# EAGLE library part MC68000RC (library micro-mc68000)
68xxx PROCESSOR

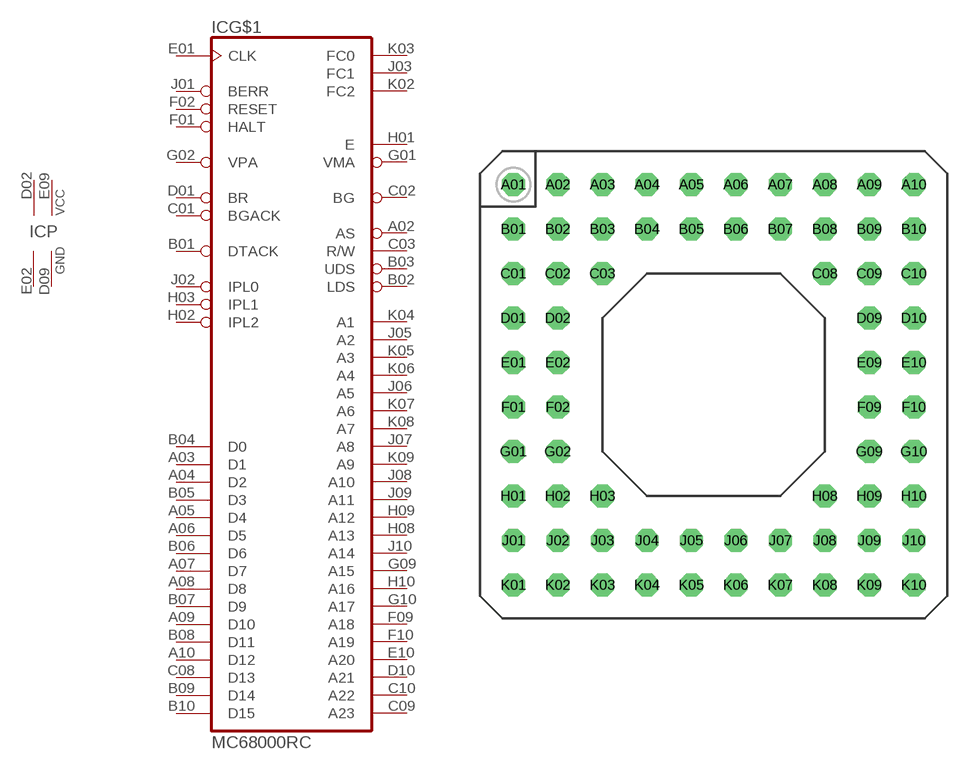
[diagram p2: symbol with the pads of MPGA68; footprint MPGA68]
Designator prefix IC; gates G$1=68000 P=2PWR2GND

## MC68000RC (MF: MOTOROLA; MPN: MC68HC000RC16; OC_FARNELL: unknown; OC_NEWARK: 40K0242)  [MPGA68]
A02  G$1:AS  out
A03  G$1:D1
A04  G$1:D2
A05  G$1:D4
A06  G$1:D5
A07  G$1:D7
A08  G$1:D8
A09  G$1:D10
A10  G$1:D12
B01  G$1:DTACK  in
B02  G$1:LDS  out
B03  G$1:UDS  out
B04  G$1:D0
B05  G$1:D3
B06  G$1:D6
B07  G$1:D9
B08  G$1:D11
B09  G$1:D14
B10  G$1:D15
C01  G$1:BGACK  in
C02  G$1:BG  out
C03  G$1:R/W  out
C08  G$1:D13
C09  G$1:A23  out
C10  G$1:A22  out
D01  G$1:BR  in
D02  P:VCC  pwr
D09  P:GND  pwr
D10  G$1:A21  out
E01  G$1:CLK  in
E02  P:GND  pwr
E09  P:VCC  pwr
E10  G$1:A20  out
F01  G$1:HALT
F02  G$1:RESET
F09  G$1:A18  out
F10  G$1:A19  out
G01  G$1:VMA  out
G02  G$1:VPA  in
G09  G$1:A15  out
G10  G$1:A17  out
H01  G$1:E  out
H02  G$1:IPL2  in
H03  G$1:IPL1  in
H08  G$1:A13  out
H09  G$1:A12  out
H10  G$1:A16  out
J01  G$1:BERR  in
J02  G$1:IPL0  in
J03  G$1:FC1  out
J05  G$1:A2  out
J06  G$1:A5  out
J07  G$1:A8  out
J08  G$1:A10  out
J09  G$1:A11  out
J10  G$1:A14  out
K02  G$1:FC2  out
K03  G$1:FC0  out
K04  G$1:A1  out
K05  G$1:A3  out
K06  G$1:A4  out
K07  G$1:A6  out
K08  G$1:A7  out
K09  G$1:A9  out

## Footprint MPGA68 (pad centres in mm)
micro Ball Grid Array
drill 0.813 octagon: A01 -11.43,11.43; A02 -8.89,11.43; A03 -6.35,11.43; A04 -3.81,11.43; A05 -1.27,11.43; A06 1.27,11.43; A07 3.81,11.43; A08 6.35,11.43; A09 8.89,11.43; A10 11.43,11.43; B01 -11.43,8.89; B02 -8.89,8.89; B03 -6.35,8.89; B04 -3.81,8.89; B05 -1.27,8.89; B06 1.27,8.89; B07 3.81,8.89; B08 6.35,8.89; B09 8.89,8.89; B10 11.43,8.89; C01 -11.43,6.35; C02 -8.89,6.35; C03 -6.35,6.35; C08 6.35,6.35; C09 8.89,6.35; C10 11.43,6.35; D01 -11.43,3.81; D02 -8.89,3.81; D09 8.89,3.81; D10 11.43,3.81; E01 -11.43,1.27; E02 -8.89,1.27; E09 8.89,1.27; E10 11.43,1.27; F01 -11.43,-1.27; F02 -8.89,-1.27; F09 8.89,-1.27; F10 11.43,-1.27; G01 -11.43,-3.81; G02 -8.89,-3.81; G09 8.89,-3.81; G10 11.43,-3.81; H01 -11.43,-6.35; H02 -8.89,-6.35; H03 -6.35,-6.35; H08 6.35,-6.35; H09 8.89,-6.35; H10 11.43,-6.35; J01 -11.43,-8.89; J02 -8.89,-8.89; J03 -6.35,-8.89; J04 -3.81,-8.89; J05 -1.27,-8.89; J06 1.27,-8.89; J07 3.81,-8.89; J08 6.35,-8.89; J09 8.89,-8.89; J10 11.43,-8.89; K01 -11.43,-11.43; K02 -8.89,-11.43; K03 -6.35,-11.43; K04 -3.81,-11.43; K05 -1.27,-11.43; K06 1.27,-11.43; K07 3.81,-11.43; K08 6.35,-11.43; K09 8.89,-11.43; K10 11.43,-11.43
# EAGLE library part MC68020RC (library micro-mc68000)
68xxx PROCESSOR

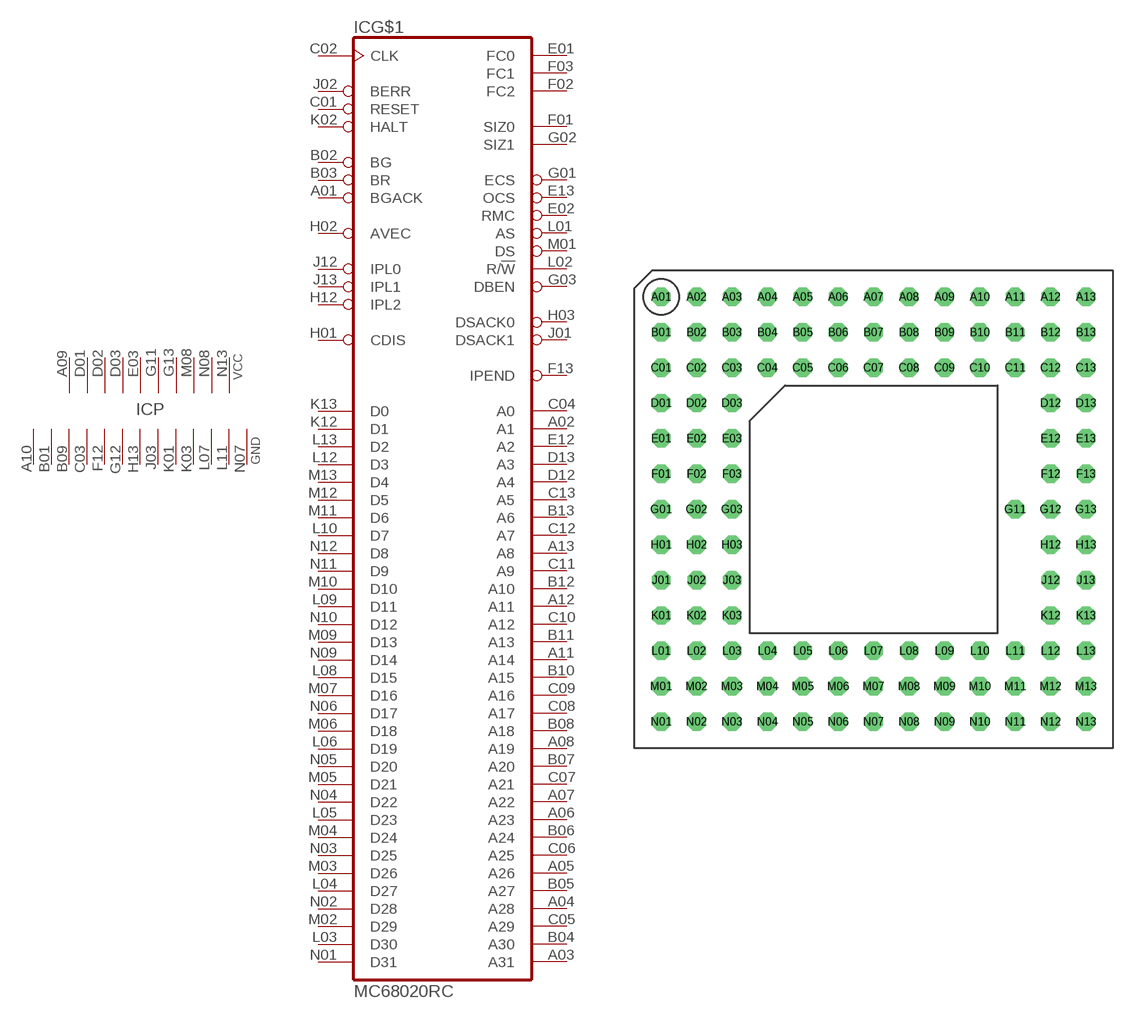
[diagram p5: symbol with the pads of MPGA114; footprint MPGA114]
Designator prefix IC; gates G$1=68020 P=10PW13GN

## MC68020RC (MF: MOTOROLA; MPN: MC68020RC33E; OC_FARNELL: 1579779; OC_NEWARK: 66F7091)  [MPGA114]
A01  G$1:BGACK  in
A02  G$1:A1  out
A03  G$1:A31  out
A04  G$1:A28  out
A05  G$1:A26  out
A06  G$1:A23  out
A07  G$1:A22  out
A08  G$1:A19  out
A09  P:VCC  pwr
A10  P:GND  pwr
A11  G$1:A14  out
A12  G$1:A11  out
A13  G$1:A8  out
B01  P:GND  pwr
B02  G$1:BG  out
B03  G$1:BR  in
B04  G$1:A30  out
B05  G$1:A27  out
B06  G$1:A24  out
B07  G$1:A20  out
B08  G$1:A18  out
B09  P:GND  pwr
B10  G$1:A15  out
B11  G$1:A13  out
B12  G$1:A10  out
B13  G$1:A6  out
C01  G$1:RESET
C02  G$1:CLK  in
C03  P:GND  pwr
C04  G$1:A0  out
C05  G$1:A29  out
C06  G$1:A25  out
C07  G$1:A21  out
C08  G$1:A17  out
C09  G$1:A16  out
C10  G$1:A12  out
C11  G$1:A9  out
C12  G$1:A7  out
C13  G$1:A5  out
D01  P:VCC  pwr
D02  P:VCC  pwr
D03  P:VCC  pwr
D12  G$1:A4  out
D13  G$1:A3  out
E01  G$1:FC0  out
E02  G$1:RMC  out
E03  P:VCC  pwr
E12  G$1:A2  out
E13  G$1:OCS  out
F01  G$1:SIZ0  out
F02  G$1:FC2  out
F03  G$1:FC1  out
F12  P:GND  pwr
F13  G$1:IPEND  out
G01  G$1:ECS  out
G02  G$1:SIZ1  out
G03  G$1:DBEN  out
G11  P:VCC  pwr
G12  P:GND  pwr
G13  P:VCC  pwr
H01  G$1:CDIS  in
H02  G$1:AVEC  in
H03  G$1:DSACK0  in
H12  G$1:IPL2  in
H13  P:GND  pwr
J01  G$1:DSACK1  in
J02  G$1:BERR  in
J03  P:GND  pwr
J12  G$1:IPL0  in
J13  G$1:IPL1  in
K01  P:GND  pwr
K02  G$1:HALT
K03  P:GND  pwr
K12  G$1:D1
K13  G$1:D0
L01  G$1:AS  out
L02  G$1:R/!W  out
L03  G$1:D30
L04  G$1:D27
L05  G$1:D23
L06  G$1:D19
L07  P:GND  pwr
L08  G$1:D15
L09  G$1:D11
L10  G$1:D7
L11  P:GND  pwr
L12  G$1:D3
L13  G$1:D2
M01  G$1:DS  out
M02  G$1:D29
M03  G$1:D26
M04  G$1:D24
M05  G$1:D21
M06  G$1:D18
M07  G$1:D16
M08  P:VCC  pwr
M09  G$1:D13
M10  G$1:D10
M11  G$1:D6
M12  G$1:D5
M13  G$1:D4
N01  G$1:D31
N02  G$1:D28
N03  G$1:D25
N04  G$1:D22
N05  G$1:D20
N06  G$1:D17
N07  P:GND  pwr
N08  P:VCC  pwr
N09  G$1:D14
N10  G$1:D12
N11  G$1:D9
N12  G$1:D8
N13  P:VCC  pwr

## Footprint MPGA114 (pad centres in mm)
micro Ball Grid Array
drill 0.813 octagon: A01 -15.24,15.24; A02 -12.7,15.24; A03 -10.16,15.24; A04 -7.62,15.24; A05 -5.08,15.24; A06 -2.54,15.24; A07 0,15.24; A08 2.54,15.24; A09 5.08,15.24; A10 7.62,15.24; A11 10.16,15.24; A12 12.7,15.24; A13 15.24,15.24; B01 -15.24,12.7; B02 -12.7,12.7; B03 -10.16,12.7; B04 -7.62,12.7; B05 -5.08,12.7; B06 -2.54,12.7; B07 0,12.7; B08 2.54,12.7; B09 5.08,12.7; B10 7.62,12.7; B11 10.16,12.7; B12 12.7,12.7; B13 15.24,12.7; C01 -15.24,10.16; C02 -12.7,10.16; C03 -10.16,10.16; C04 -7.62,10.16; C05 -5.08,10.16; C06 -2.54,10.16; C07 0,10.16; C08 2.54,10.16; C09 5.08,10.16; C10 7.62,10.16; C11 10.16,10.16; C12 12.7,10.16; C13 15.24,10.16; D01 -15.24,7.62; D02 -12.7,7.62; D03 -10.16,7.62; D12 12.7,7.62; D13 15.24,7.62; E01 -15.24,5.08; E02 -12.7,5.08; E03 -10.16,5.08; E12 12.7,5.08; E13 15.24,5.08; F01 -15.24,2.54; F02 -12.7,2.54; F03 -10.16,2.54; F12 12.7,2.54; F13 15.24,2.54; G01 -15.24,0; G02 -12.7,0; G03 -10.16,0; G11 10.16,0; G12 12.7,0; G13 15.24,0; H01 -15.24,-2.54; H02 -12.7,-2.54; H03 -10.16,-2.54; H12 12.7,-2.54; H13 15.24,-2.54; J01 -15.24,-5.08; J02 -12.7,-5.08; J03 -10.16,-5.08; J12 12.7,-5.08; J13 15.24,-5.08; K01 -15.24,-7.62; K02 -12.7,-7.62; K03 -10.16,-7.62; K12 12.7,-7.62; K13 15.24,-7.62; L01 -15.24,-10.16; L02 -12.7,-10.16; L03 -10.16,-10.16; L04 -7.62,-10.16; L05 -5.08,-10.16; L06 -2.54,-10.16; L07 0,-10.16; L08 2.54,-10.16; L09 5.08,-10.16; L10 7.62,-10.16; L11 10.16,-10.16; L12 12.7,-10.16; L13 15.24,-10.16; M01 -15.24,-12.7; M02 -12.7,-12.7; M03 -10.16,-12.7; M04 -7.62,-12.7; M05 -5.08,-12.7; M06 -2.54,-12.7; M07 0,-12.7; M08 2.54,-12.7; M09 5.08,-12.7; M10 7.62,-12.7; M11 10.16,-12.7; M12 12.7,-12.7; M13 15.24,-12.7; N01 -15.24,-15.24; N02 -12.7,-15.24; N03 -10.16,-15.24; N04 -7.62,-15.24; N05 -5.08,-15.24; N06 -2.54,-15.24; N07 0,-15.24; N08 2.54,-15.24; N09 5.08,-15.24; N10 7.62,-15.24; N11 10.16,-15.24; N12 12.7,-15.24; N13 15.24,-15.24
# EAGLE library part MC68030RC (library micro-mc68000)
68xxx PROCESSOR

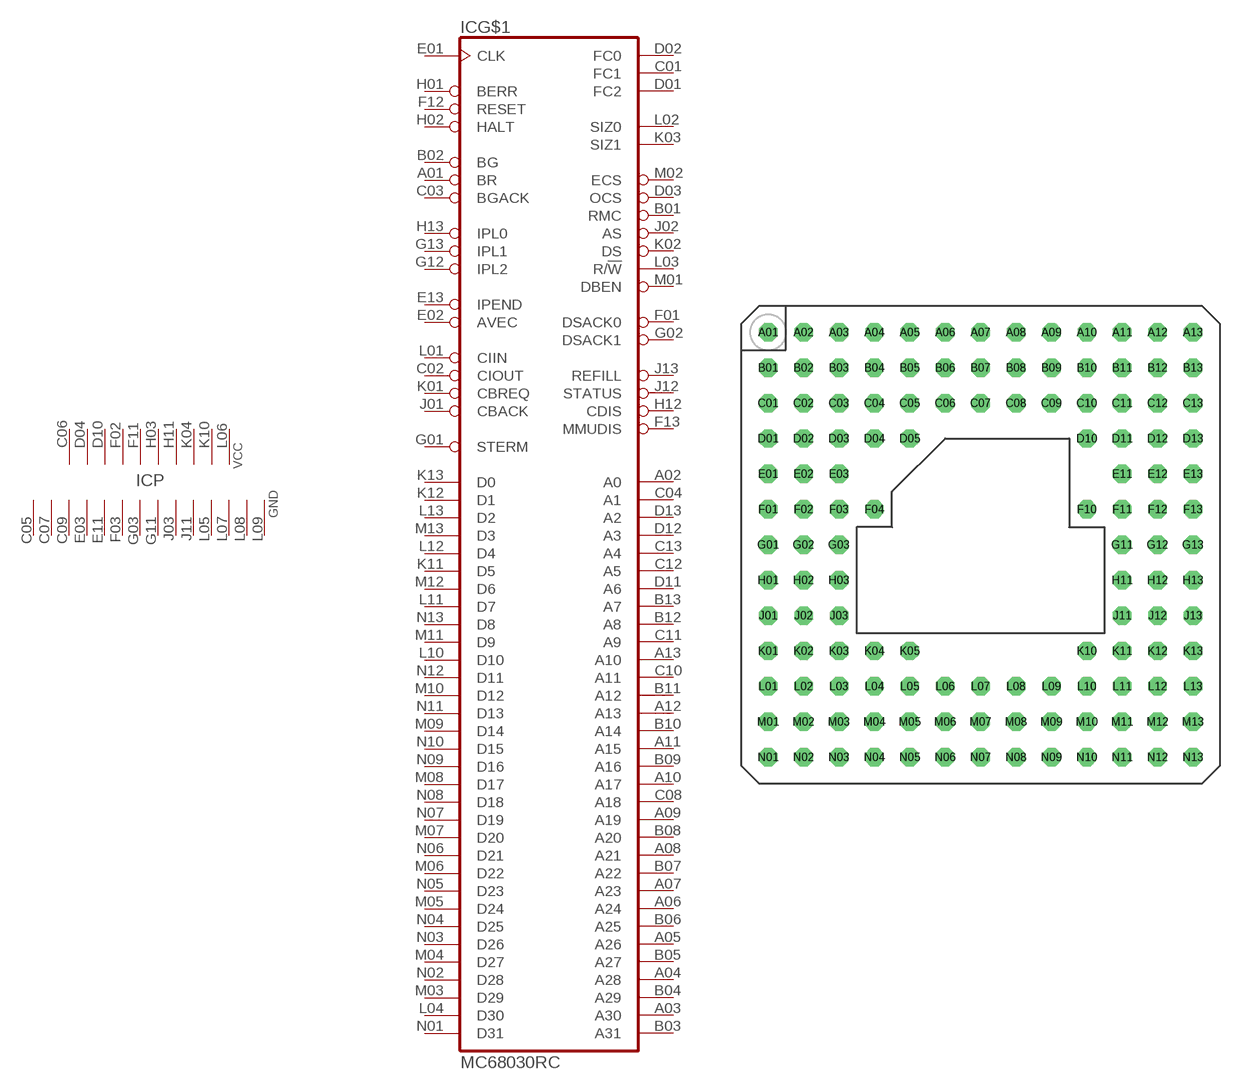
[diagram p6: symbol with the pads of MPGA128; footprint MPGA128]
Designator prefix IC; gates G$1=68030 P=10PW14GN

## MC68030RC (MF: MOTOROLA; MPN: MC68030RC50C; OC_FARNELL: unknown; OC_NEWARK: 52F3269)  [MPGA128]
A01  G$1:BR  in
A02  G$1:A0  out
A03  G$1:A30  out
A04  G$1:A28  out
A05  G$1:A26  out
A06  G$1:A24  out
A07  G$1:A23  out
A08  G$1:A21  out
A09  G$1:A19  out
A10  G$1:A17  out
A11  G$1:A15  out
A12  G$1:A13  out
A13  G$1:A10  out
B01  G$1:RMC  out
B02  G$1:BG  out
B03  G$1:A31  out
B04  G$1:A29  out
B05  G$1:A27  out
B06  G$1:A25  out
B07  G$1:A22  out
B08  G$1:A20  out
B09  G$1:A16  out
B10  G$1:A14  out
B11  G$1:A12  out
B12  G$1:A8  out
B13  G$1:A7  out
C01  G$1:FC1  out
C02  G$1:CIOUT  out
C03  G$1:BGACK  in
C04  G$1:A1  out
C05  P:GND  pwr
C06  P:VCC  pwr
C07  P:GND  pwr
C08  G$1:A18  out
C09  P:GND  pwr
C10  G$1:A11  out
C11  G$1:A9  out
C12  G$1:A5  out
C13  G$1:A4  out
D01  G$1:FC2  out
D02  G$1:FC0  out
D03  G$1:OCS  out
D04  P:VCC  pwr
D10  P:VCC  pwr
D11  G$1:A6  out
D12  G$1:A3  out
D13  G$1:A2  out
E01  G$1:CLK  in
E02  G$1:AVEC  in
E03  P:GND  pwr
E11  P:GND  pwr
E13  G$1:IPEND  out
F01  G$1:DSACK0  in
F02  P:VCC  pwr
F03  P:GND  pwr
F11  P:VCC  pwr
F12  G$1:RESET
F13  G$1:MMUDIS  in
G01  G$1:STERM  in
G02  G$1:DSACK1  in
G03  P:GND  pwr
G11  P:GND  pwr
G12  G$1:IPL2  in
G13  G$1:IPL1  in
H01  G$1:BERR  in
H02  G$1:HALT  in
H03  P:VCC  pwr
H11  P:VCC  pwr
H12  G$1:CDIS  in
H13  G$1:IPL0  in
J01  G$1:CBACK  in
J02  G$1:AS  out
J03  P:GND  pwr
J11  P:GND  pwr
J12  G$1:STATUS  out
J13  G$1:REFILL  out
K01  G$1:CBREQ  out
K02  G$1:DS  out
K03  G$1:SIZ1  out
K04  P:VCC  pwr
K10  P:VCC  pwr
K11  G$1:D5
K12  G$1:D1
K13  G$1:D0
L01  G$1:CIIN  in
L02  G$1:SIZ0  out
L03  G$1:R/!W  out
L04  G$1:D30
L05  P:GND  pwr
L06  P:VCC  pwr
L07  P:GND  pwr
L08  P:GND  pwr
L09  P:GND  pwr
L10  G$1:D10
L11  G$1:D7
L12  G$1:D4
L13  G$1:D2
M01  G$1:DBEN  out
M02  G$1:ECS  out
M03  G$1:D29
M04  G$1:D27
M05  G$1:D24
M06  G$1:D22
M07  G$1:D20
M08  G$1:D17
M09  G$1:D14
M10  G$1:D12
M11  G$1:D9
M12  G$1:D6
M13  G$1:D3
N01  G$1:D31
N02  G$1:D28
N03  G$1:D26
N04  G$1:D25
N05  G$1:D23
N06  G$1:D21
N07  G$1:D19
N08  G$1:D18
N09  G$1:D16
N10  G$1:D15
N11  G$1:D13
N12  G$1:D11
N13  G$1:D8

## Footprint MPGA128 (pad centres in mm)
micro Ball Grid Array
drill 0.813 octagon: A01 -15.24,15.24; A02 -12.7,15.24; A03 -10.16,15.24; A04 -7.62,15.24; A05 -5.08,15.24; A06 -2.54,15.24; A07 0,15.24; A08 2.54,15.24; A09 5.08,15.24; A10 7.62,15.24; A11 10.16,15.24; A12 12.7,15.24; A13 15.24,15.24; B01 -15.24,12.7; B02 -12.7,12.7; B03 -10.16,12.7; B04 -7.62,12.7; B05 -5.08,12.7; B06 -2.54,12.7; B07 0,12.7; B08 2.54,12.7; B09 5.08,12.7; B10 7.62,12.7; B11 10.16,12.7; B12 12.7,12.7; B13 15.24,12.7; C01 -15.24,10.16; C02 -12.7,10.16; C03 -10.16,10.16; C04 -7.62,10.16; C05 -5.08,10.16; C06 -2.54,10.16; C07 0,10.16; C08 2.54,10.16; C09 5.08,10.16; C10 7.62,10.16; C11 10.16,10.16; C12 12.7,10.16; C13 15.24,10.16; D01 -15.24,7.62; D02 -12.7,7.62; D03 -10.16,7.62; D04 -7.62,7.62; D05 -5.08,7.62; D10 7.62,7.62; D11 10.16,7.62; D12 12.7,7.62; D13 15.24,7.62; E01 -15.24,5.08; E02 -12.7,5.08; E03 -10.16,5.08; E11 10.16,5.08; E12 12.7,5.08; E13 15.24,5.08; F01 -15.24,2.54; F02 -12.7,2.54; F03 -10.16,2.54; F04 -7.62,2.54; F10 7.62,2.54; F11 10.16,2.54; F12 12.7,2.54; F13 15.24,2.54; G01 -15.24,0; G02 -12.7,0; G03 -10.16,0; G11 10.16,0; G12 12.7,0; G13 15.24,0; H01 -15.24,-2.54; H02 -12.7,-2.54; H03 -10.16,-2.54; H11 10.16,-2.54; H12 12.7,-2.54; H13 15.24,-2.54; J01 -15.24,-5.08; J02 -12.7,-5.08; J03 -10.16,-5.08; J11 10.16,-5.08; J12 12.7,-5.08; J13 15.24,-5.08; K01 -15.24,-7.62; K02 -12.7,-7.62; K03 -10.16,-7.62; K04 -7.62,-7.62; K05 -5.08,-7.62; K10 7.62,-7.62; K11 10.16,-7.62; K12 12.7,-7.62; K13 15.24,-7.62; L01 -15.24,-10.16; L02 -12.7,-10.16; L03 -10.16,-10.16; L04 -7.62,-10.16; L05 -5.08,-10.16; L06 -2.54,-10.16; L07 0,-10.16; L08 2.54,-10.16; L09 5.08,-10.16; L10 7.62,-10.16; L11 10.16,-10.16; L12 12.7,-10.16; L13 15.24,-10.16; M01 -15.24,-12.7; M02 -12.7,-12.7; M03 -10.16,-12.7; M04 -7.62,-12.7; M05 -5.08,-12.7; M06 -2.54,-12.7; M07 0,-12.7; M08 2.54,-12.7; M09 5.08,-12.7; M10 7.62,-12.7; M11 10.16,-12.7; M12 12.7,-12.7; M13 15.24,-12.7; N01 -15.24,-15.24; N02 -12.7,-15.24; N03 -10.16,-15.24; N04 -7.62,-15.24; N05 -5.08,-15.24; N06 -2.54,-15.24; N07 0,-15.24; N08 2.54,-15.24; N09 5.08,-15.24; N10 7.62,-15.24; N11 10.16,-15.24; N12 12.7,-15.24; N13 15.24,-15.24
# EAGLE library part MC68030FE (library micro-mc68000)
68xxx PROCESSOR

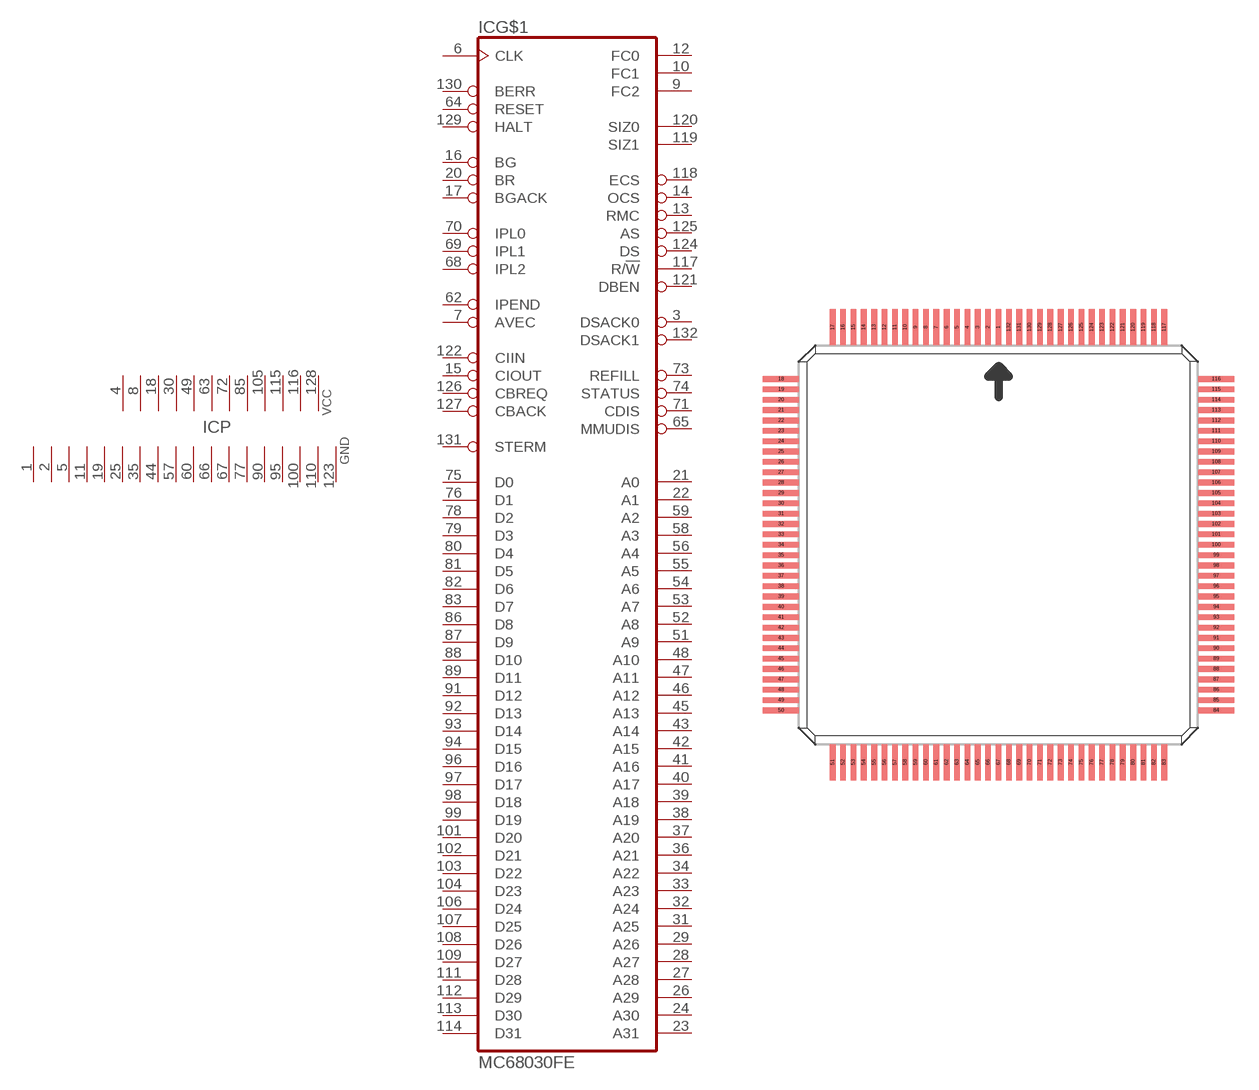
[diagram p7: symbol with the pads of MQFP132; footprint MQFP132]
Designator prefix IC; gates G$1=68030 P=12PW18GN

## MC68030FE (MF: MOTOROLA; MPN: MC68030FE33C; OC_FARNELL: unknown; OC_NEWARK: 52F3266)  [MQFP132]
1  P:GND  pwr
2  P:GND  pwr
3  G$1:DSACK0  in
4  P:VCC  pwr
5  P:GND  pwr
6  G$1:CLK  in
7  G$1:AVEC  in
8  P:VCC  pwr
9  G$1:FC2  out
10  G$1:FC1  out
11  P:GND  pwr
12  G$1:FC0  out
13  G$1:RMC  out
14  G$1:OCS  out
15  G$1:CIOUT  out
16  G$1:BG  out
17  G$1:BGACK  in
18  P:VCC  pwr
19  P:GND  pwr
20  G$1:BR  in
21  G$1:A0  out
22  G$1:A1  out
23  G$1:A31  out
24  G$1:A30  out
25  P:GND  pwr
26  G$1:A29  out
27  G$1:A28  out
28  G$1:A27  out
29  G$1:A26  out
30  P:VCC  pwr
31  G$1:A25  out
32  G$1:A24  out
33  G$1:A23  out
34  G$1:A22  out
35  P:GND  pwr
36  G$1:A21  out
37  G$1:A20  out
38  G$1:A19  out
39  G$1:A18  out
40  G$1:A17  out
41  G$1:A16  out
42  G$1:A15  out
43  G$1:A14  out
44  P:GND  pwr
45  G$1:A13  out
46  G$1:A12  out
47  G$1:A11  out
48  G$1:A10  out
49  P:VCC  pwr
51  G$1:A9  out
52  G$1:A8  out
53  G$1:A7  out
54  G$1:A6  out
55  G$1:A5  out
56  G$1:A4  out
57  P:GND  pwr
58  G$1:A3  out
59  G$1:A2  out
60  P:GND  pwr
62  G$1:IPEND  out
63  P:VCC  pwr
64  G$1:RESET
65  G$1:MMUDIS  in
66  P:GND  pwr
67  P:GND  pwr
68  G$1:IPL2  in
69  G$1:IPL1  in
70  G$1:IPL0  in
71  G$1:CDIS  in
72  P:VCC  pwr
73  G$1:REFILL  out
74  G$1:STATUS  out
75  G$1:D0
76  G$1:D1
77  P:GND  pwr
78  G$1:D2
79  G$1:D3
80  G$1:D4
81  G$1:D5
82  G$1:D6
83  G$1:D7
85  P:VCC  pwr
86  G$1:D8
87  G$1:D9
88  G$1:D10
89  G$1:D11
90  P:GND  pwr
91  G$1:D12
92  G$1:D13
93  G$1:D14
94  G$1:D15
95  P:GND  pwr
96  G$1:D16
97  G$1:D17
98  G$1:D18
99  G$1:D19
100  P:GND  pwr
101  G$1:D20
102  G$1:D21
103  G$1:D22
104  G$1:D23
105  P:VCC  pwr
106  G$1:D24
107  G$1:D25
108  G$1:D26
109  G$1:D27
110  P:GND  pwr
111  G$1:D28
112  G$1:D29
113  G$1:D30
114  G$1:D31
115  P:VCC  pwr
116  P:VCC  pwr
117  G$1:R/!W  out
118  G$1:ECS  out
119  G$1:SIZ1  out
120  G$1:SIZ0  out
121  G$1:DBEN  out
122  G$1:CIIN  in
123  P:GND  pwr
124  G$1:DS  out
125  G$1:AS  out
126  G$1:CBREQ  out
127  G$1:CBACK  in
128  P:VCC  pwr
129  G$1:HALT  in
130  G$1:BERR  in
131  G$1:STERM  in
132  G$1:DSACK1  in

## Footprint MQFP132 (pad centres in mm)
Metric Quad Flat Pack
smd 0.35 x 2.2: 1 0,12.7; 2 -0.635,12.7; 3 -1.27,12.7; 4 -1.905,12.7; 5 -2.54,12.7; 6 -3.175,12.7; 7 -3.81,12.7; 8 -4.445,12.7; 9 -5.08,12.7; 10 -5.715,12.7; 11 -6.35,12.7; 12 -6.985,12.7; 13 -7.62,12.7; 14 -8.255,12.7; 15 -8.89,12.7; 16 -9.525,12.7; 17 -10.16,12.7; 51 -10.16,-13.97; 52 -9.525,-13.97; 53 -8.89,-13.97; 54 -8.255,-13.97; 55 -7.62,-13.97; 56 -6.985,-13.97; 57 -6.35,-13.97; 58 -5.715,-13.97; 59 -5.08,-13.97; 60 -4.445,-13.97; 61 -3.81,-13.97; 62 -3.175,-13.97; 63 -2.54,-13.97; 64 -1.905,-13.97; 65 -1.27,-13.97; 66 -0.635,-13.97; 67 0,-13.97; 68 0.635,-13.97; 69 1.27,-13.97; 70 1.905,-13.97; 71 2.54,-13.97; 72 3.175,-13.97; 73 3.81,-13.97; 74 4.445,-13.97; 75 5.08,-13.97; 76 5.715,-13.97; 77 6.35,-13.97; 78 6.985,-13.97; 79 7.62,-13.97; 80 8.255,-13.97; 81 8.89,-13.97; 82 9.525,-13.97; 83 10.16,-13.97; 117 10.16,12.7; 118 9.525,12.7; 119 8.89,12.7; 120 8.255,12.7; 121 7.62,12.7; 122 6.985,12.7; 123 6.35,12.7; 124 5.715,12.7; 125 5.08,12.7; 126 4.445,12.7; 127 3.81,12.7; 128 3.175,12.7; 129 2.54,12.7; 130 1.905,12.7; 131 1.27,12.7; 132 0.635,12.7
smd 2.2 x 0.35: 18 -13.335,9.525; 19 -13.335,8.89; 20 -13.335,8.255; 21 -13.335,7.62; 22 -13.335,6.985; 23 -13.335,6.35; 24 -13.335,5.715; 25 -13.335,5.08; 26 -13.335,4.445; 27 -13.335,3.81; 28 -13.335,3.175; 29 -13.335,2.54; 30 -13.335,1.905; 31 -13.335,1.27; 32 -13.335,0.635; 33 -13.335,0; 34 -13.335,-0.635; 35 -13.335,-1.27; 36 -13.335,-1.905; 37 -13.335,-2.54; 38 -13.335,-3.175; 39 -13.335,-3.81; 40 -13.335,-4.445; 41 -13.335,-5.08; 42 -13.335,-5.715; 43 -13.335,-6.35; 44 -13.335,-6.985; 45 -13.335,-7.62; 46 -13.335,-8.255; 47 -13.335,-8.89; 48 -13.335,-9.525; 49 -13.335,-10.16; 50 -13.335,-10.795; 84 13.335,-10.795; 85 13.335,-10.16; 86 13.335,-9.525; 87 13.335,-8.89; 88 13.335,-8.255; 89 13.335,-7.62; 90 13.335,-6.985; 91 13.335,-6.35; 92 13.335,-5.715; 93 13.335,-5.08; 94 13.335,-4.445; 95 13.335,-3.81; 96 13.335,-3.175; 97 13.335,-2.54; 98 13.335,-1.905; 99 13.335,-1.27; 100 13.335,-0.635; 101 13.335,0; 102 13.335,0.635; 103 13.335,1.27; 104 13.335,1.905; 105 13.335,2.54; 106 13.335,3.175; 107 13.335,3.81; 108 13.335,4.445; 109 13.335,5.08; 110 13.335,5.715; 111 13.335,6.35; 112 13.335,6.985; 113 13.335,7.62; 114 13.335,8.255; 115 13.335,8.89; 116 13.335,9.525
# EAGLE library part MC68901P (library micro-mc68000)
68xxx PROCESSOR

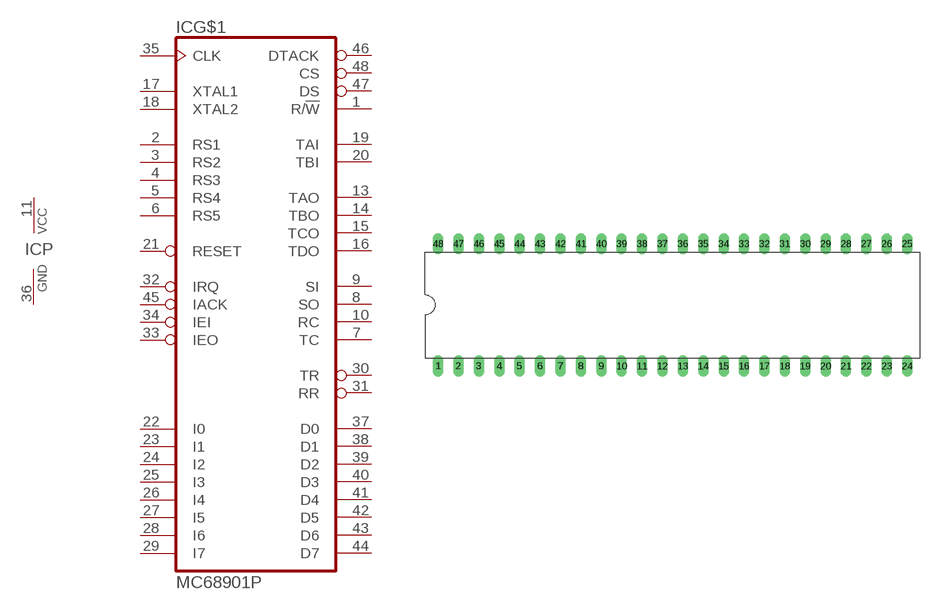
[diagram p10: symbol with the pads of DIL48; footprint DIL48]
Designator prefix IC; gates G$1=68901 P=PWRN

## MC68901P (OC_FARNELL: unknown; OC_NEWARK: unknown)  [DIL48]
1  G$1:R/!W  in
2  G$1:RS1  in
3  G$1:RS2  in
4  G$1:RS3  in
5  G$1:RS4  in
6  G$1:RS5  in
7  G$1:TC  in
8  G$1:SO  out
9  G$1:SI  in
10  G$1:RC  in
11  P:VCC  pwr
13  G$1:TAO  out
14  G$1:TBO  out
15  G$1:TCO  out
16  G$1:TDO  out
17  G$1:XTAL1  in
18  G$1:XTAL2  in
19  G$1:TAI  in
20  G$1:TBI  in
21  G$1:RESET  in
22  G$1:I0
23  G$1:I1
24  G$1:I2
25  G$1:I3
26  G$1:I4
27  G$1:I5
28  G$1:I6
29  G$1:I7
30  G$1:TR  out
31  G$1:RR  out
32  G$1:IRQ  out
33  G$1:IEO  out
34  G$1:IEI  in
35  G$1:CLK  in
36  P:GND  pwr
37  G$1:D0
38  G$1:D1
39  G$1:D2
40  G$1:D3
41  G$1:D4
42  G$1:D5
43  G$1:D6
44  G$1:D7
45  G$1:IACK  in
46  G$1:DTACK  out
47  G$1:DS  in
48  G$1:CS  in

## Footprint DIL48 (pad centres in mm)
Dual In Line
drill 0.813 long: 1 -29.21,-7.62; 2 -26.67,-7.62; 3 -24.13,-7.62; 4 -21.59,-7.62; 5 -19.05,-7.62; 6 -16.51,-7.62; 7 -13.97,-7.62; 8 -11.43,-7.62; 9 -8.89,-7.62; 10 -6.35,-7.62; 11 -3.81,-7.62; 12 -1.27,-7.62; 13 1.27,-7.62; 14 3.81,-7.62; 15 6.35,-7.62; 16 8.89,-7.62; 17 11.43,-7.62; 18 13.97,-7.62; 19 16.51,-7.62; 20 19.05,-7.62; 21 21.59,-7.62; 22 24.13,-7.62; 23 26.67,-7.62; 24 29.21,-7.62; 25 29.21,7.62; 26 26.67,7.62; 27 24.13,7.62; 28 21.59,7.62; 29 19.05,7.62; 30 16.51,7.62; 31 13.97,7.62; 32 11.43,7.62; 33 8.89,7.62; 34 6.35,7.62; 35 3.81,7.62; 36 1.27,7.62; 37 -1.27,7.62; 38 -3.81,7.62; 39 -6.35,7.62; 40 -8.89,7.62; 41 -11.43,7.62; 42 -13.97,7.62; 43 -16.51,7.62; 44 -19.05,7.62; 45 -21.59,7.62; 46 -24.13,7.62; 47 -26.67,7.62; 48 -29.21,7.62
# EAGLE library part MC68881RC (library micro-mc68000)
68xxx PROCESSOR

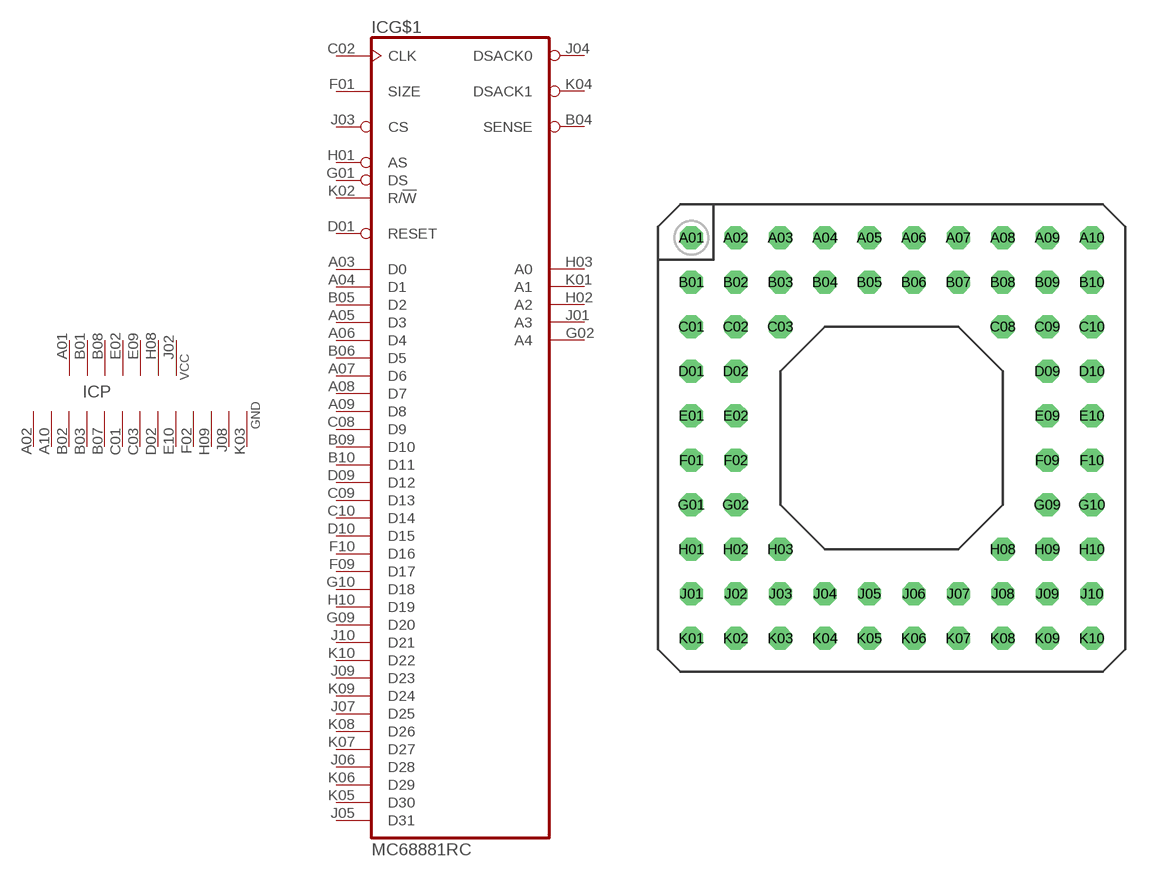
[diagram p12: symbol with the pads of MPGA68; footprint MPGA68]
Designator prefix IC; gates G$1=68881 P=7PWR13GN

## MC68881RC (OC_FARNELL: unknown; OC_NEWARK: unknown)  [MPGA68]
A01  P:VCC  pwr
A02  P:GND  pwr
A03  G$1:D0
A04  G$1:D1
A05  G$1:D3
A06  G$1:D4
A07  G$1:D6
A08  G$1:D7
A09  G$1:D8
A10  P:GND  pwr
B01  P:VCC  pwr
B02  P:GND  pwr
B03  P:GND  pwr
B04  G$1:SENSE
B05  G$1:D2
B06  G$1:D5
B07  P:GND  pwr
B08  P:VCC  pwr
B09  G$1:D10
B10  G$1:D11
C01  P:GND  pwr
C02  G$1:CLK  in
C03  P:GND  pwr
C08  G$1:D9
C09  G$1:D13
C10  G$1:D14
D01  G$1:RESET  in
D02  P:GND  pwr
D09  G$1:D12
D10  G$1:D15
E02  P:VCC  pwr
E09  P:VCC  pwr
E10  P:GND  pwr
F01  G$1:SIZE  in
F02  P:GND  pwr
F09  G$1:D17
F10  G$1:D16
G01  G$1:DS  in
G02  G$1:A4  in
G09  G$1:D20
G10  G$1:D18
H01  G$1:AS  in
H02  G$1:A2  in
H03  G$1:A0  in
H08  P:VCC  pwr
H09  P:GND  pwr
H10  G$1:D19
J01  G$1:A3  in
J02  P:VCC  pwr
J03  G$1:CS  in
J04  G$1:DSACK0  out
J05  G$1:D31
J06  G$1:D28
J07  G$1:D25
J08  P:GND  pwr
J09  G$1:D23
J10  G$1:D21
K01  G$1:A1  in
K02  G$1:R/!W  in
K03  P:GND  pwr
K04  G$1:DSACK1  out
K05  G$1:D30
K06  G$1:D29
K07  G$1:D27
K08  G$1:D26
K09  G$1:D24
K10  G$1:D22

## Footprint MPGA68 (pad centres in mm)
micro Ball Grid Array
drill 0.813 octagon: A01 -11.43,11.43; A02 -8.89,11.43; A03 -6.35,11.43; A04 -3.81,11.43; A05 -1.27,11.43; A06 1.27,11.43; A07 3.81,11.43; A08 6.35,11.43; A09 8.89,11.43; A10 11.43,11.43; B01 -11.43,8.89; B02 -8.89,8.89; B03 -6.35,8.89; B04 -3.81,8.89; B05 -1.27,8.89; B06 1.27,8.89; B07 3.81,8.89; B08 6.35,8.89; B09 8.89,8.89; B10 11.43,8.89; C01 -11.43,6.35; C02 -8.89,6.35; C03 -6.35,6.35; C08 6.35,6.35; C09 8.89,6.35; C10 11.43,6.35; D01 -11.43,3.81; D02 -8.89,3.81; D09 8.89,3.81; D10 11.43,3.81; E01 -11.43,1.27; E02 -8.89,1.27; E09 8.89,1.27; E10 11.43,1.27; F01 -11.43,-1.27; F02 -8.89,-1.27; F09 8.89,-1.27; F10 11.43,-1.27; G01 -11.43,-3.81; G02 -8.89,-3.81; G09 8.89,-3.81; G10 11.43,-3.81; H01 -11.43,-6.35; H02 -8.89,-6.35; H03 -6.35,-6.35; H08 6.35,-6.35; H09 8.89,-6.35; H10 11.43,-6.35; J01 -11.43,-8.89; J02 -8.89,-8.89; J03 -6.35,-8.89; J04 -3.81,-8.89; J05 -1.27,-8.89; J06 1.27,-8.89; J07 3.81,-8.89; J08 6.35,-8.89; J09 8.89,-8.89; J10 11.43,-8.89; K01 -11.43,-11.43; K02 -8.89,-11.43; K03 -6.35,-11.43; K04 -3.81,-11.43; K05 -1.27,-11.43; K06 1.27,-11.43; K07 3.81,-11.43; K08 6.35,-11.43; K09 8.89,-11.43; K10 11.43,-11.43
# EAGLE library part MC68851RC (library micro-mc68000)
68xxx PROCESSOR

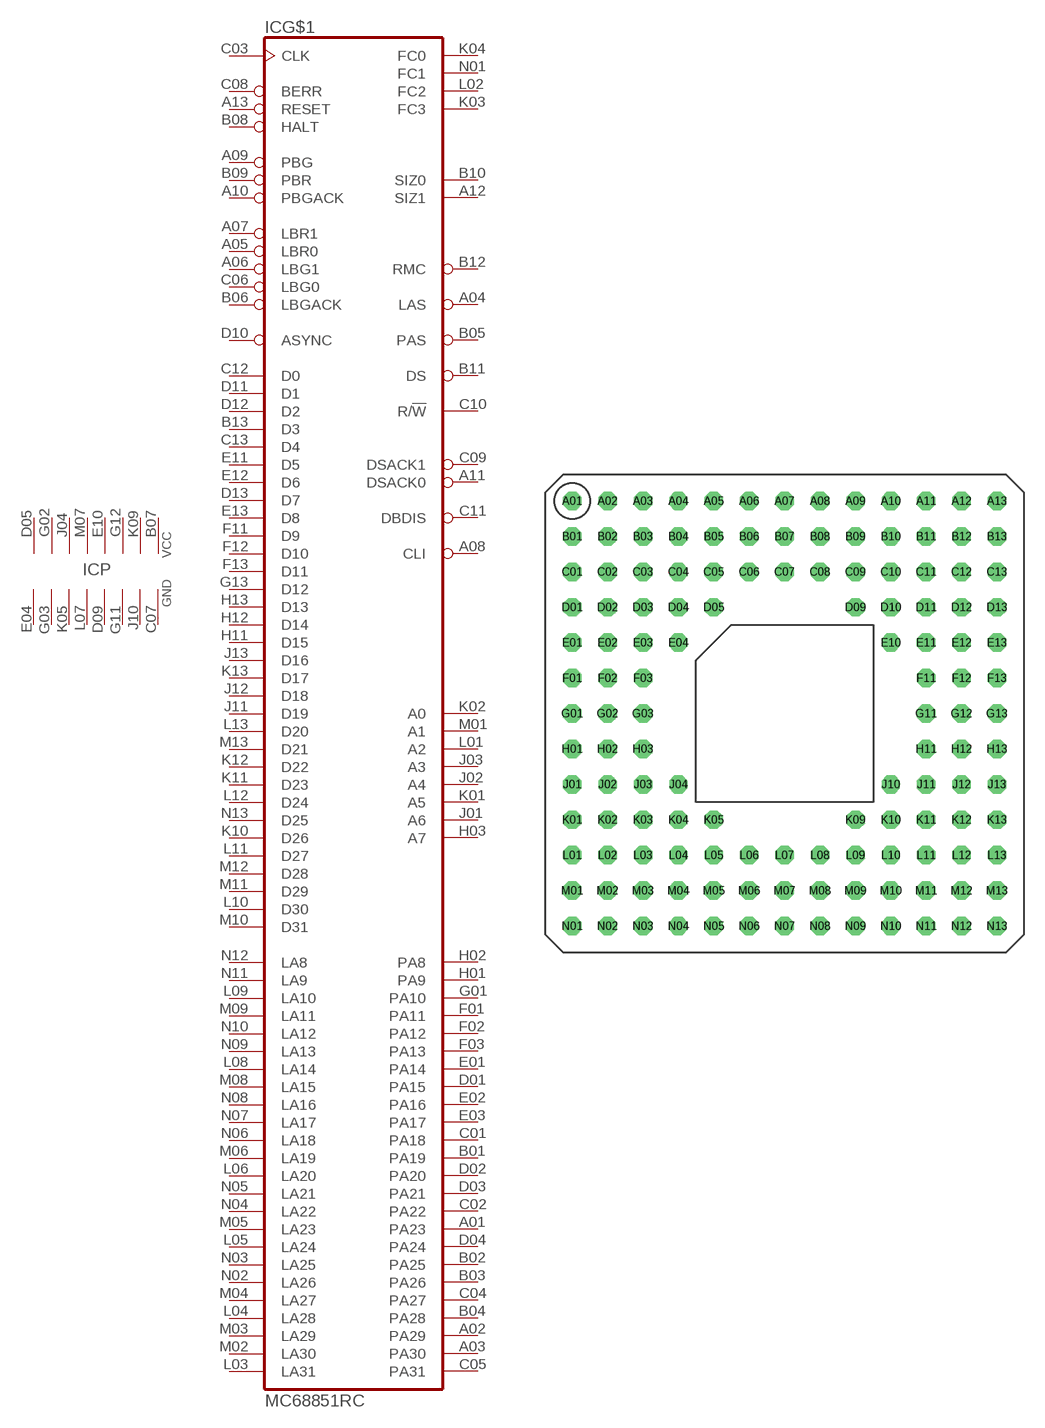
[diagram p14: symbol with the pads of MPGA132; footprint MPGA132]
Designator prefix IC; gates G$1=68851 P=8PWR8GND

## MC68851RC (OC_FARNELL: unknown; OC_NEWARK: unknown)  [MPGA132]
A01  G$1:PA23  out
A02  G$1:PA29  out
A03  G$1:PA30  out
A04  G$1:LAS  in
A05  G$1:LBR0  out
A06  G$1:LBG1  in
A07  G$1:LBR1  in
A08  G$1:CLI  out
A09  G$1:PBG  out
A10  G$1:PBGACK  in
A11  G$1:DSACK0
A12  G$1:SIZ1
A13  G$1:RESET  in
B01  G$1:PA19  out
B02  G$1:PA25  out
B03  G$1:PA26  out
B04  G$1:PA28  out
B05  G$1:PAS  out
B06  G$1:LBGACK
B07  P:VCC  pwr
B08  G$1:HALT
B09  G$1:PBR  in
B10  G$1:SIZ0
B11  G$1:DS
B12  G$1:RMC
B13  G$1:D3
C01  G$1:PA18  out
C02  G$1:PA22  out
C03  G$1:CLK  in
C04  G$1:PA27  out
C05  G$1:PA31  out
C06  G$1:LBG0  out
C07  P:GND  pwr
C08  G$1:BERR
C09  G$1:DSACK1
C10  G$1:R/!W
C11  G$1:DBDIS  out
C12  G$1:D0
C13  G$1:D4
D01  G$1:PA15  out
D02  G$1:PA20  out
D03  G$1:PA21  out
D04  G$1:PA24  out
D05  P:VCC  pwr
D09  P:GND  pwr
D10  G$1:ASYNC  in
D11  G$1:D1
D12  G$1:D2
D13  G$1:D7
E01  G$1:PA14  out
E02  G$1:PA16  out
E03  G$1:PA17  out
E04  P:GND  pwr
E10  P:VCC  pwr
E11  G$1:D5
E12  G$1:D6
E13  G$1:D8
F01  G$1:PA11  out
F02  G$1:PA12  out
F03  G$1:PA13  out
F11  G$1:D9
F12  G$1:D10
F13  G$1:D11
G01  G$1:PA10  out
G02  P:VCC  pwr
G03  P:GND  pwr
G11  P:GND  pwr
G12  P:VCC  pwr
G13  G$1:D12
H01  G$1:PA9  out
H02  G$1:PA8  out
H03  G$1:A7
H11  G$1:D15
H12  G$1:D14
H13  G$1:D13
J01  G$1:A6
J02  G$1:A4
J03  G$1:A3
J04  P:VCC  pwr
J10  P:GND  pwr
J11  G$1:D19
J12  G$1:D18
J13  G$1:D16
K01  G$1:A5
K02  G$1:A0
K03  G$1:FC3
K04  G$1:FC0
K05  P:GND  pwr
K09  P:VCC  pwr
K10  G$1:D26
K11  G$1:D23
K12  G$1:D22
K13  G$1:D17
L01  G$1:A2
L02  G$1:FC2
L03  G$1:LA31  in
L04  G$1:LA28  in
L05  G$1:LA24  in
L06  G$1:LA20  in
L07  P:GND  pwr
L08  G$1:LA14  in
L09  G$1:LA10  in
L10  G$1:D30
L11  G$1:D27
L12  G$1:D24
L13  G$1:D20
M01  G$1:A1
M02  G$1:LA30  in
M03  G$1:LA29  in
M04  G$1:LA27  in
M05  G$1:LA23  in
M06  G$1:LA19  in
M07  P:VCC  pwr
M08  G$1:LA15  in
M09  G$1:LA11  in
M10  G$1:D31
M11  G$1:D29
M12  G$1:D28
M13  G$1:D21
N01  G$1:FC1
N02  G$1:LA26  in
N03  G$1:LA25  in
N04  G$1:LA22  in
N05  G$1:LA21  in
N06  G$1:LA18  in
N07  G$1:LA17  in
N08  G$1:LA16  in
N09  G$1:LA13  in
N10  G$1:LA12  in
N11  G$1:LA9  in
N12  G$1:LA8  in
N13  G$1:D25

## Footprint MPGA132 (pad centres in mm)
micro Ball Grid Array
drill 0.813 octagon: A01 -15.24,15.24; A02 -12.7,15.24; A03 -10.16,15.24; A04 -7.62,15.24; A05 -5.08,15.24; A06 -2.54,15.24; A07 0,15.24; A08 2.54,15.24; A09 5.08,15.24; A10 7.62,15.24; A11 10.16,15.24; A12 12.7,15.24; A13 15.24,15.24; B01 -15.24,12.7; B02 -12.7,12.7; B03 -10.16,12.7; B04 -7.62,12.7; B05 -5.08,12.7; B06 -2.54,12.7; B07 0,12.7; B08 2.54,12.7; B09 5.08,12.7; B10 7.62,12.7; B11 10.16,12.7; B12 12.7,12.7; B13 15.24,12.7; C01 -15.24,10.16; C02 -12.7,10.16; C03 -10.16,10.16; C04 -7.62,10.16; C05 -5.08,10.16; C06 -2.54,10.16; C07 0,10.16; C08 2.54,10.16; C09 5.08,10.16; C10 7.62,10.16; C11 10.16,10.16; C12 12.7,10.16; C13 15.24,10.16; D01 -15.24,7.62; D02 -12.7,7.62; D03 -10.16,7.62; D04 -7.62,7.62; D05 -5.08,7.62; D09 5.08,7.62; D10 7.62,7.62; D11 10.16,7.62; D12 12.7,7.62; D13 15.24,7.62; E01 -15.24,5.08; E02 -12.7,5.08; E03 -10.16,5.08; E04 -7.62,5.08; E10 7.62,5.08; E11 10.16,5.08; E12 12.7,5.08; E13 15.24,5.08; F01 -15.24,2.54; F02 -12.7,2.54; F03 -10.16,2.54; F11 10.16,2.54; F12 12.7,2.54; F13 15.24,2.54; G01 -15.24,0; G02 -12.7,0; G03 -10.16,0; G11 10.16,0; G12 12.7,0; G13 15.24,0; H01 -15.24,-2.54; H02 -12.7,-2.54; H03 -10.16,-2.54; H11 10.16,-2.54; H12 12.7,-2.54; H13 15.24,-2.54; J01 -15.24,-5.08; J02 -12.7,-5.08; J03 -10.16,-5.08; J04 -7.62,-5.08; J10 7.62,-5.08; J11 10.16,-5.08; J12 12.7,-5.08; J13 15.24,-5.08; K01 -15.24,-7.62; K02 -12.7,-7.62; K03 -10.16,-7.62; K04 -7.62,-7.62; K05 -5.08,-7.62; K09 5.08,-7.62; K10 7.62,-7.62; K11 10.16,-7.62; K12 12.7,-7.62; K13 15.24,-7.62; L01 -15.24,-10.16; L02 -12.7,-10.16; L03 -10.16,-10.16; L04 -7.62,-10.16; L05 -5.08,-10.16; L06 -2.54,-10.16; L07 0,-10.16; L08 2.54,-10.16; L09 5.08,-10.16; L10 7.62,-10.16; L11 10.16,-10.16; L12 12.7,-10.16; L13 15.24,-10.16; M01 -15.24,-12.7; M02 -12.7,-12.7; M03 -10.16,-12.7; M04 -7.62,-12.7; M05 -5.08,-12.7; M06 -2.54,-12.7; M07 0,-12.7; M08 2.54,-12.7; M09 5.08,-12.7; M10 7.62,-12.7; M11 10.16,-12.7; M12 12.7,-12.7; M13 15.24,-12.7; N01 -15.24,-15.24; N02 -12.7,-15.24; N03 -10.16,-15.24; N04 -7.62,-15.24; N05 -5.08,-15.24; N06 -2.54,-15.24; N07 0,-15.24; N08 2.54,-15.24; N09 5.08,-15.24; N10 7.62,-15.24; N11 10.16,-15.24; N12 12.7,-15.24; N13 15.24,-15.24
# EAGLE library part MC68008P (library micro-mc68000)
68xxx PROCESSOR

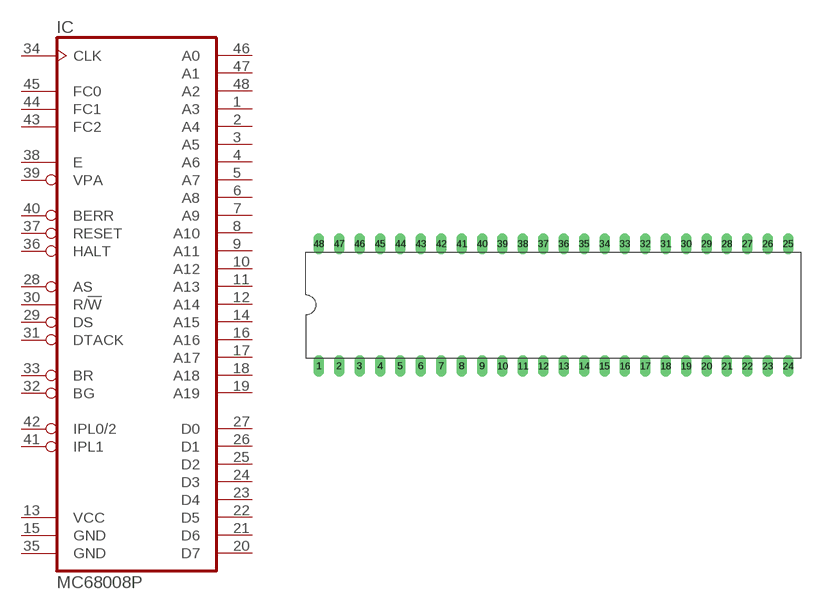
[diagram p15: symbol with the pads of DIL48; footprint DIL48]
Designator prefix IC

## MC68008P (OC_FARNELL: unknown; OC_NEWARK: unknown)  [DIL48]
1  A3  out
2  A4  out
3  A5  out
4  A6  out
5  A7  out
6  A8  out
7  A9  out
8  A10  out
9  A11  out
10  A12  out
11  A13  out
12  A14  out
13  VCC  pwr
14  A15  out
15  GND  pwr
16  A16  out
17  A17  out
18  A18  out
19  A19  out
20  D7
21  D6
22  D5
23  D4
24  D3
25  D2
26  D1
27  D0
28  AS  out
29  DS  out
30  R/!W  out
31  DTACK  in
32  BG  out
33  BR  in
34  CLK  in
35  GND  pwr
36  HALT
37  RESET
38  E  out
39  VPA  in
40  BERR  in
41  IPL1  in
42  IPL0/2  in
43  FC2  out
44  FC1  out
45  FC0  out
46  A0  out
47  A1  out
48  A2  out

## Footprint DIL48 (pad centres in mm)
Dual In Line
drill 0.813 long: 1 -29.21,-7.62; 2 -26.67,-7.62; 3 -24.13,-7.62; 4 -21.59,-7.62; 5 -19.05,-7.62; 6 -16.51,-7.62; 7 -13.97,-7.62; 8 -11.43,-7.62; 9 -8.89,-7.62; 10 -6.35,-7.62; 11 -3.81,-7.62; 12 -1.27,-7.62; 13 1.27,-7.62; 14 3.81,-7.62; 15 6.35,-7.62; 16 8.89,-7.62; 17 11.43,-7.62; 18 13.97,-7.62; 19 16.51,-7.62; 20 19.05,-7.62; 21 21.59,-7.62; 22 24.13,-7.62; 23 26.67,-7.62; 24 29.21,-7.62; 25 29.21,7.62; 26 26.67,7.62; 27 24.13,7.62; 28 21.59,7.62; 29 19.05,7.62; 30 16.51,7.62; 31 13.97,7.62; 32 11.43,7.62; 33 8.89,7.62; 34 6.35,7.62; 35 3.81,7.62; 36 1.27,7.62; 37 -1.27,7.62; 38 -3.81,7.62; 39 -6.35,7.62; 40 -8.89,7.62; 41 -11.43,7.62; 42 -13.97,7.62; 43 -16.51,7.62; 44 -19.05,7.62; 45 -21.59,7.62; 46 -24.13,7.62; 47 -26.67,7.62; 48 -29.21,7.62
